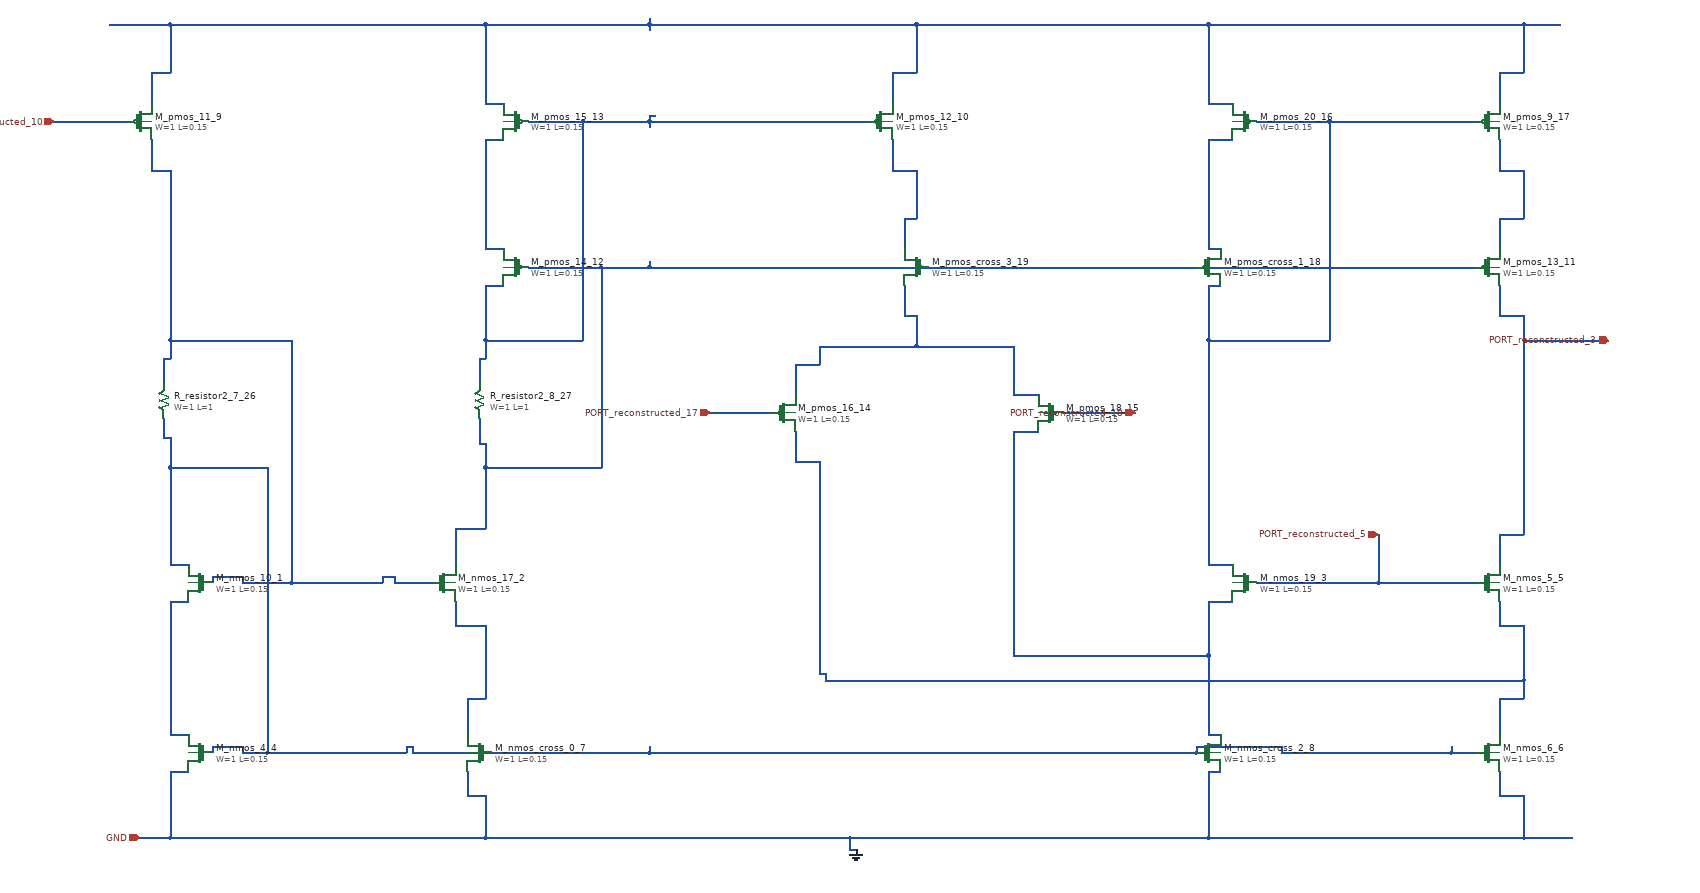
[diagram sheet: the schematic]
v {xschem version=3.4.8 file_version=1.2}
G {}
K {}
V {}
S {}
E {}
C {devices/gnd.sym} 1420 1440 0 0 {name="l_gnd_24_0" lab="GND"}
C {sky130_fd_pr/nfet3_01v8.sym} 340 1000 0 1 {name="M_nmos_10_1"
W=1
L=0.15
body=GND
nf=1
mult=1
ad="expr('int((@nf + 1)/2) * @W / @nf * 0.29')"
pd="expr('2*int((@nf + 1)/2) * (@W / @nf + 0.29)')"
as="expr('int((@nf + 2)/2) * @W / @nf * 0.29')"
ps="expr('2*int((@nf + 2)/2) * (@W / @nf + 0.29)')"
nrd="expr('0.29 / @W ')" nrs="expr('0.29 / @W ')"
sa=0 sb=0 sd=0
model=nfet_01v8
spiceprefix=X
}
C {sky130_fd_pr/nfet3_01v8.sym} 740 1000 0 0 {name="M_nmos_17_2"
W=1
L=0.15
body=GND
nf=1
mult=1
ad="expr('int((@nf + 1)/2) * @W / @nf * 0.29')"
pd="expr('2*int((@nf + 1)/2) * (@W / @nf + 0.29)')"
as="expr('int((@nf + 2)/2) * @W / @nf * 0.29')"
ps="expr('2*int((@nf + 2)/2) * (@W / @nf + 0.29)')"
nrd="expr('0.29 / @W ')" nrs="expr('0.29 / @W ')"
sa=0 sb=0 sd=0
model=nfet_01v8
spiceprefix=X
}
C {sky130_fd_pr/nfet3_01v8.sym} 2060 1000 0 1 {name="M_nmos_19_3"
W=1
L=0.15
body=GND
nf=1
mult=1
ad="expr('int((@nf + 1)/2) * @W / @nf * 0.29')"
pd="expr('2*int((@nf + 1)/2) * (@W / @nf + 0.29)')"
as="expr('int((@nf + 2)/2) * @W / @nf * 0.29')"
ps="expr('2*int((@nf + 2)/2) * (@W / @nf + 0.29)')"
nrd="expr('0.29 / @W ')" nrs="expr('0.29 / @W ')"
sa=0 sb=0 sd=0
model=nfet_01v8
spiceprefix=X
}
C {sky130_fd_pr/nfet3_01v8.sym} 340 1280 0 1 {name="M_nmos_4_4"
W=1
L=0.15
body=GND
nf=1
mult=1
ad="expr('int((@nf + 1)/2) * @W / @nf * 0.29')"
pd="expr('2*int((@nf + 1)/2) * (@W / @nf + 0.29)')"
as="expr('int((@nf + 2)/2) * @W / @nf * 0.29')"
ps="expr('2*int((@nf + 2)/2) * (@W / @nf + 0.29)')"
nrd="expr('0.29 / @W ')" nrs="expr('0.29 / @W ')"
sa=0 sb=0 sd=0
model=nfet_01v8
spiceprefix=X
}
C {sky130_fd_pr/nfet3_01v8.sym} 2460 1000 0 0 {name="M_nmos_5_5"
W=1
L=0.15
body=GND
nf=1
mult=1
ad="expr('int((@nf + 1)/2) * @W / @nf * 0.29')"
pd="expr('2*int((@nf + 1)/2) * (@W / @nf + 0.29)')"
as="expr('int((@nf + 2)/2) * @W / @nf * 0.29')"
ps="expr('2*int((@nf + 2)/2) * (@W / @nf + 0.29)')"
nrd="expr('0.29 / @W ')" nrs="expr('0.29 / @W ')"
sa=0 sb=0 sd=0
model=nfet_01v8
spiceprefix=X
}
C {sky130_fd_pr/nfet3_01v8.sym} 2460 1280 0 0 {name="M_nmos_6_6"
W=1
L=0.15
body=GND
nf=1
mult=1
ad="expr('int((@nf + 1)/2) * @W / @nf * 0.29')"
pd="expr('2*int((@nf + 1)/2) * (@W / @nf + 0.29)')"
as="expr('int((@nf + 2)/2) * @W / @nf * 0.29')"
ps="expr('2*int((@nf + 2)/2) * (@W / @nf + 0.29)')"
nrd="expr('0.29 / @W ')" nrs="expr('0.29 / @W ')"
sa=0 sb=0 sd=0
model=nfet_01v8
spiceprefix=X
}
C {sky130_fd_pr/nfet3_01v8.sym} 800 1280 0 1 {name="M_nmos_cross_0_7"
W=1
L=0.15
body=GND
nf=1
mult=1
ad="expr('int((@nf + 1)/2) * @W / @nf * 0.29')"
pd="expr('2*int((@nf + 1)/2) * (@W / @nf + 0.29)')"
as="expr('int((@nf + 2)/2) * @W / @nf * 0.29')"
ps="expr('2*int((@nf + 2)/2) * (@W / @nf + 0.29)')"
nrd="expr('0.29 / @W ')" nrs="expr('0.29 / @W ')"
sa=0 sb=0 sd=0
model=nfet_01v8
spiceprefix=X
}
C {sky130_fd_pr/nfet3_01v8.sym} 2000 1280 0 0 {name="M_nmos_cross_2_8"
W=1
L=0.15
body=GND
nf=1
mult=1
ad="expr('int((@nf + 1)/2) * @W / @nf * 0.29')"
pd="expr('2*int((@nf + 1)/2) * (@W / @nf + 0.29)')"
as="expr('int((@nf + 2)/2) * @W / @nf * 0.29')"
ps="expr('2*int((@nf + 2)/2) * (@W / @nf + 0.29)')"
nrd="expr('0.29 / @W ')" nrs="expr('0.29 / @W ')"
sa=0 sb=0 sd=0
model=nfet_01v8
spiceprefix=X
}
C {sky130_fd_pr/pfet3_01v8.sym} 240 240 0 0 {name="M_pmos_11_9"
W=1
L=0.15
body=VDD
nf=1
mult=1
ad="expr('int((@nf + 1)/2) * @W / @nf * 0.29')"
pd="expr('2*int((@nf + 1)/2) * (@W / @nf + 0.29)')"
as="expr('int((@nf + 2)/2) * @W / @nf * 0.29')"
ps="expr('2*int((@nf + 2)/2) * (@W / @nf + 0.29)')"
nrd="expr('0.29 / @W ')" nrs="expr('0.29 / @W ')"
sa=0 sb=0 sd=0
model=pfet_01v8
spiceprefix=X
}
C {sky130_fd_pr/pfet3_01v8.sym} 1460 240 0 0 {name="M_pmos_12_10"
W=1
L=0.15
body=VDD
nf=1
mult=1
ad="expr('int((@nf + 1)/2) * @W / @nf * 0.29')"
pd="expr('2*int((@nf + 1)/2) * (@W / @nf + 0.29)')"
as="expr('int((@nf + 2)/2) * @W / @nf * 0.29')"
ps="expr('2*int((@nf + 2)/2) * (@W / @nf + 0.29)')"
nrd="expr('0.29 / @W ')" nrs="expr('0.29 / @W ')"
sa=0 sb=0 sd=0
model=pfet_01v8
spiceprefix=X
}
C {sky130_fd_pr/pfet3_01v8.sym} 2460 480 0 0 {name="M_pmos_13_11"
W=1
L=0.15
body=VDD
nf=1
mult=1
ad="expr('int((@nf + 1)/2) * @W / @nf * 0.29')"
pd="expr('2*int((@nf + 1)/2) * (@W / @nf + 0.29)')"
as="expr('int((@nf + 2)/2) * @W / @nf * 0.29')"
ps="expr('2*int((@nf + 2)/2) * (@W / @nf + 0.29)')"
nrd="expr('0.29 / @W ')" nrs="expr('0.29 / @W ')"
sa=0 sb=0 sd=0
model=pfet_01v8
spiceprefix=X
}
C {sky130_fd_pr/pfet3_01v8.sym} 860 480 0 1 {name="M_pmos_14_12"
W=1
L=0.15
body=VDD
nf=1
mult=1
ad="expr('int((@nf + 1)/2) * @W / @nf * 0.29')"
pd="expr('2*int((@nf + 1)/2) * (@W / @nf + 0.29)')"
as="expr('int((@nf + 2)/2) * @W / @nf * 0.29')"
ps="expr('2*int((@nf + 2)/2) * (@W / @nf + 0.29)')"
nrd="expr('0.29 / @W ')" nrs="expr('0.29 / @W ')"
sa=0 sb=0 sd=0
model=pfet_01v8
spiceprefix=X
}
C {sky130_fd_pr/pfet3_01v8.sym} 860 240 0 1 {name="M_pmos_15_13"
W=1
L=0.15
body=VDD
nf=1
mult=1
ad="expr('int((@nf + 1)/2) * @W / @nf * 0.29')"
pd="expr('2*int((@nf + 1)/2) * (@W / @nf + 0.29)')"
as="expr('int((@nf + 2)/2) * @W / @nf * 0.29')"
ps="expr('2*int((@nf + 2)/2) * (@W / @nf + 0.29)')"
nrd="expr('0.29 / @W ')" nrs="expr('0.29 / @W ')"
sa=0 sb=0 sd=0
model=pfet_01v8
spiceprefix=X
}
C {sky130_fd_pr/pfet3_01v8.sym} 1300 720 0 0 {name="M_pmos_16_14"
W=1
L=0.15
body=VDD
nf=1
mult=1
ad="expr('int((@nf + 1)/2) * @W / @nf * 0.29')"
pd="expr('2*int((@nf + 1)/2) * (@W / @nf + 0.29)')"
as="expr('int((@nf + 2)/2) * @W / @nf * 0.29')"
ps="expr('2*int((@nf + 2)/2) * (@W / @nf + 0.29)')"
nrd="expr('0.29 / @W ')" nrs="expr('0.29 / @W ')"
sa=0 sb=0 sd=0
model=pfet_01v8
spiceprefix=X
}
C {sky130_fd_pr/pfet3_01v8.sym} 1740 720 0 1 {name="M_pmos_18_15"
W=1
L=0.15
body=VDD
nf=1
mult=1
ad="expr('int((@nf + 1)/2) * @W / @nf * 0.29')"
pd="expr('2*int((@nf + 1)/2) * (@W / @nf + 0.29)')"
as="expr('int((@nf + 2)/2) * @W / @nf * 0.29')"
ps="expr('2*int((@nf + 2)/2) * (@W / @nf + 0.29)')"
nrd="expr('0.29 / @W ')" nrs="expr('0.29 / @W ')"
sa=0 sb=0 sd=0
model=pfet_01v8
spiceprefix=X
}
C {sky130_fd_pr/pfet3_01v8.sym} 2060 240 0 1 {name="M_pmos_20_16"
W=1
L=0.15
body=VDD
nf=1
mult=1
ad="expr('int((@nf + 1)/2) * @W / @nf * 0.29')"
pd="expr('2*int((@nf + 1)/2) * (@W / @nf + 0.29)')"
as="expr('int((@nf + 2)/2) * @W / @nf * 0.29')"
ps="expr('2*int((@nf + 2)/2) * (@W / @nf + 0.29)')"
nrd="expr('0.29 / @W ')" nrs="expr('0.29 / @W ')"
sa=0 sb=0 sd=0
model=pfet_01v8
spiceprefix=X
}
C {sky130_fd_pr/pfet3_01v8.sym} 2460 240 0 0 {name="M_pmos_9_17"
W=1
L=0.15
body=VDD
nf=1
mult=1
ad="expr('int((@nf + 1)/2) * @W / @nf * 0.29')"
pd="expr('2*int((@nf + 1)/2) * (@W / @nf + 0.29)')"
as="expr('int((@nf + 2)/2) * @W / @nf * 0.29')"
ps="expr('2*int((@nf + 2)/2) * (@W / @nf + 0.29)')"
nrd="expr('0.29 / @W ')" nrs="expr('0.29 / @W ')"
sa=0 sb=0 sd=0
model=pfet_01v8
spiceprefix=X
}
C {sky130_fd_pr/pfet3_01v8.sym} 2000 480 0 0 {name="M_pmos_cross_1_18"
W=1
L=0.15
body=VDD
nf=1
mult=1
ad="expr('int((@nf + 1)/2) * @W / @nf * 0.29')"
pd="expr('2*int((@nf + 1)/2) * (@W / @nf + 0.29)')"
as="expr('int((@nf + 2)/2) * @W / @nf * 0.29')"
ps="expr('2*int((@nf + 2)/2) * (@W / @nf + 0.29)')"
nrd="expr('0.29 / @W ')" nrs="expr('0.29 / @W ')"
sa=0 sb=0 sd=0
model=pfet_01v8
spiceprefix=X
}
C {sky130_fd_pr/pfet3_01v8.sym} 1520 480 0 1 {name="M_pmos_cross_3_19"
W=1
L=0.15
body=VDD
nf=1
mult=1
ad="expr('int((@nf + 1)/2) * @W / @nf * 0.29')"
pd="expr('2*int((@nf + 1)/2) * (@W / @nf + 0.29)')"
as="expr('int((@nf + 2)/2) * @W / @nf * 0.29')"
ps="expr('2*int((@nf + 2)/2) * (@W / @nf + 0.29)')"
nrd="expr('0.29 / @W ')" nrs="expr('0.29 / @W ')"
sa=0 sb=0 sd=0
model=pfet_01v8
spiceprefix=X
}
C {devices/ipin.sym} 1880 720 0 0 {name="p_port_21_20" lab="PORT_reconstructed_18"}
C {devices/ipin.sym} 1180 720 0 0 {name="p_port_22_21" lab="PORT_reconstructed_17"}
C {devices/ipin.sym} 2660 600 0 0 {name="p_port_23_22" lab="PORT_reconstructed_3"}
C {devices/ipin.sym} 2280 920 0 0 {name="p_port_25_23" lab="PORT_reconstructed_5"}
C {devices/ipin.sym} 100 240 0 0 {name="p_port_26_24" lab="PORT_reconstructed_10"}
C {devices/ipin.sym} 240 1420 0 0 {name="p_port_32_25" lab="GND"}
C {sky130_fd_pr/res_generic_po.sym} 280 700 2 0 {name="R_resistor2_7_26"
W=1
L=1
model=res_generic_po
spiceprefix=X
mult=1}
C {sky130_fd_pr/res_generic_po.sym} 800 700 2 0 {name="R_resistor2_8_27"
W=1
L=1
model=res_generic_po
spiceprefix=X
mult=1}
N 1410 1440 1420 1440 {}
N 240 1420 290 1420 {}
N 290 1420 810 1420 {}
N 810 1420 1410 1420 {}
N 1410 1420 2000 1420 {}
N 2000 1420 2520 1420 {}
N 2520 1420 2600 1420 {}
N 780 1350 810 1350 {}
N 2480 1350 2520 1350 {}
N 290 1310 320 1310 {}
N 2000 1310 2020 1310 {}
N 290 1420 290 1310 {}
N 780 1350 780 1310 {}
N 810 1420 810 1350 {}
N 1410 1440 1410 1420 {}
N 2000 1420 2000 1310 {}
N 2480 1350 2480 1310 {}
N 2520 1420 2520 1350 {}
N 290 1250 320 1250 {}
N 290 1030 320 1030 {}
N 290 1250 290 1030 {}
N 100 240 220 240 {}
N 1500 400 1520 400 {}
N 1480 320 1520 320 {}
N 1480 320 1480 270 {}
N 1500 450 1500 400 {}
N 1520 400 1520 320 {}
N 800 630 810 630 {}
N 810 600 970 600 {}
N 810 510 840 510 {}
N 880 240 970 240 {}
N 970 240 1080 240 {}
N 1080 240 1440 240 {}
N 1080 230 1090 230 {}
N 800 670 800 630 {}
N 810 630 810 600 {}
N 810 600 810 510 {}
N 970 600 970 240 {}
N 1080 250 1080 240 {}
N 1080 240 1080 230 {}
N 2480 400 2520 400 {}
N 2480 320 2520 320 {}
N 2480 450 2480 400 {}
N 2480 320 2480 270 {}
N 2520 400 2520 320 {}
N 760 910 810 910 {}
N 810 810 1000 810 {}
N 800 770 810 770 {}
N 880 480 1000 480 {}
N 1000 480 1080 480 {}
N 1080 480 1540 480 {}
N 1540 480 1980 480 {}
N 1980 480 2440 480 {}
N 760 970 760 910 {}
N 800 770 800 730 {}
N 810 910 810 810 {}
N 810 810 810 770 {}
N 1000 810 1000 480 {}
N 1080 480 1080 470 {}
N 810 450 840 450 {}
N 810 270 840 270 {}
N 810 450 810 270 {}
N 1680 690 1720 690 {}
N 1320 640 1360 640 {}
N 1360 610 1520 610 {}
N 1520 610 1680 610 {}
N 1500 560 1520 560 {}
N 1320 690 1320 640 {}
N 1360 640 1360 610 {}
N 1500 560 1500 510 {}
N 1520 610 1520 560 {}
N 1680 690 1680 610 {}
N 1170 720 1180 720 {}
N 1180 720 1280 720 {}
N 1760 720 1880 720 {}
N 2000 450 2020 450 {}
N 2000 270 2040 270 {}
N 2000 450 2000 270 {}
N 410 1280 450 1280 {}
N 450 1280 680 1280 {}
N 690 1280 820 1280 {}
N 820 1280 1080 1280 {}
N 1080 1280 1980 1280 {}
N 1980 1280 1990 1280 {}
N 2120 1280 2400 1280 {}
N 2400 1280 2440 1280 {}
N 360 1270 410 1270 {}
N 680 1270 690 1270 {}
N 1980 1270 2120 1270 {}
N 290 970 320 970 {}
N 290 810 450 810 {}
N 280 760 290 760 {}
N 280 760 280 730 {}
N 290 970 290 810 {}
N 290 810 290 760 {}
N 360 1280 360 1270 {}
N 410 1280 410 1270 {}
N 450 1280 450 810 {}
N 680 1280 680 1270 {}
N 690 1280 690 1270 {}
N 1080 1280 1080 1270 {}
N 1980 1280 1980 1270 {}
N 2120 1280 2120 1270 {}
N 2400 1280 2400 1270 {}
N 2000 970 2040 970 {}
N 2000 600 2200 600 {}
N 2000 510 2020 510 {}
N 2080 240 2200 240 {}
N 2200 240 2440 240 {}
N 2000 970 2000 600 {}
N 2000 600 2000 510 {}
N 2200 600 2200 240 {}
N 2480 920 2520 920 {}
N 2520 600 2660 600 {}
N 2480 560 2520 560 {}
N 2480 970 2480 920 {}
N 2480 560 2480 510 {}
N 2520 920 2520 600 {}
N 2520 600 2520 560 {}
N 2480 1190 2520 1190 {}
N 1370 1160 2520 1160 {}
N 1360 1150 1370 1150 {}
N 2480 1070 2520 1070 {}
N 1320 800 1360 800 {}
N 1320 800 1320 750 {}
N 1360 1150 1360 800 {}
N 1370 1160 1370 1150 {}
N 2480 1250 2480 1190 {}
N 2480 1070 2480 1030 {}
N 2520 1190 2520 1160 {}
N 2520 1160 2520 1070 {}
N 2080 1000 2280 1000 {}
N 2280 1000 2440 1000 {}
N 2280 1000 2280 920 {}
N 780 1190 810 1190 {}
N 760 1070 810 1070 {}
N 760 1070 760 1030 {}
N 780 1250 780 1190 {}
N 810 1190 810 1070 {}
N 2000 1250 2020 1250 {}
N 1680 1120 2000 1120 {}
N 2000 1030 2040 1030 {}
N 1680 750 1720 750 {}
N 1680 1120 1680 750 {}
N 2000 1250 2000 1120 {}
N 2000 1120 2000 1030 {}
N 810 210 840 210 {}
N 2000 210 2040 210 {}
N 260 160 290 160 {}
N 1480 160 1520 160 {}
N 2480 160 2520 160 {}
N 190 80 290 80 {}
N 290 80 810 80 {}
N 810 80 1080 80 {}
N 1080 80 1520 80 {}
N 1520 80 2000 80 {}
N 2000 80 2520 80 {}
N 2520 80 2580 80 {}
N 260 210 260 160 {}
N 290 160 290 80 {}
N 810 210 810 80 {}
N 1080 90 1080 80 {}
N 1080 80 1080 70 {}
N 1480 210 1480 160 {}
N 1520 160 1520 80 {}
N 2000 210 2000 80 {}
N 2480 210 2480 160 {}
N 2520 160 2520 80 {}
N 410 1000 490 1000 {}
N 490 1000 640 1000 {}
N 660 1000 720 1000 {}
N 360 990 410 990 {}
N 640 990 660 990 {}
N 280 630 290 630 {}
N 290 600 490 600 {}
N 260 320 290 320 {}
N 260 320 260 270 {}
N 280 670 280 630 {}
N 290 630 290 600 {}
N 290 600 290 320 {}
N 360 1000 360 990 {}
N 410 1000 410 990 {}
N 490 1000 490 600 {}
N 640 1000 640 990 {}
N 660 1000 660 990 {}
